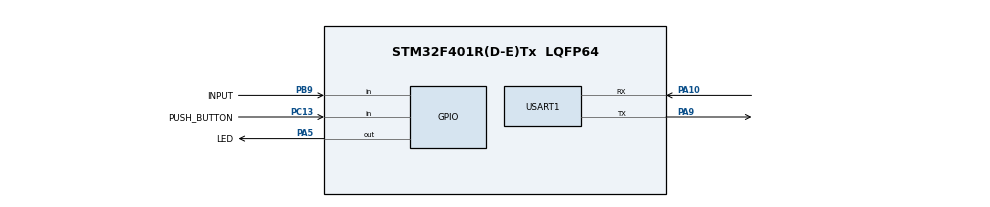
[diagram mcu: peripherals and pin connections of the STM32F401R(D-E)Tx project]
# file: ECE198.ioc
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Mcu.Family=STM32F4
Mcu.Name=STM32F401R(D-E)Tx
Mcu.Package=LQFP64
NVIC.PriorityGroup=NVIC_PRIORITYGROUP_0
NVIC.USART1_IRQn=true\:0\:0\:false\:false\:true\:true\:true\:true
PA10.Mode=Asynchronous
PA10.Signal=USART1_RX
PA13.GPIO_Label=TMS
PA13.Mode=Serial_Wire
PA13.Signal=SYS_JTMS-SWDIO
PA14.GPIO_Label=TCK
PA14.Mode=Serial_Wire
PA14.Signal=SYS_JTCK-SWCLK
PA5.GPIO_Label=LED
PA5.GPIO_Speed=GPIO_SPEED_FREQ_VERY_HIGH
PA5.Signal=GPIO_Output
PA9.Mode=Asynchronous
PA9.Signal=USART1_TX
PB9.GPIO_Label=INPUT
PB9.GPIO_PuPd=GPIO_PULLDOWN
PB9.Signal=GPIO_Input
PC13-ANTI_TAMP.GPIO_Label=PUSH_BUTTON
PC13-ANTI_TAMP.Signal=GPIO_Input
PC14-OSC32_IN.Signal=RCC_OSC32_IN
PC15-OSC32_OUT.Signal=RCC_OSC32_OUT
PH0\ -\ OSC_IN.Mode=HSE-External-Oscillator
PH0\ -\ OSC_IN.Signal=RCC_OSC_IN
PH1\ -\ OSC_OUT.Mode=HSE-External-Oscillator
PH1\ -\ OSC_OUT.Signal=RCC_OSC_OUT
ProjectManager.HeapSize=0x200
ProjectManager.StackSize=0x400
ProjectManager.TargetToolchain=STM32CubeIDE
RCC.48MHZClocksFreq_Value=48000000
RCC.AHBFreq_Value=84000000
RCC.APB1CLKDivider=RCC_HCLK_DIV2
RCC.APB1Freq_Value=42000000
RCC.APB1TimFreq_Value=84000000
RCC.APB2Freq_Value=84000000
RCC.APB2TimFreq_Value=84000000
RCC.CortexFreq_Value=84000000
RCC.HCLKFreq_Value=84000000
RCC.HSE_VALUE=8000000
RCC.HSI_VALUE=16000000
RCC.LSE_VALUE=32768
RCC.PLLN=336
RCC.PLLP=RCC_PLLP_DIV4
RCC.PLLQ=7
RCC.SYSCLKFreq_VALUE=84000000
RCC.SYSCLKSource=RCC_SYSCLKSOURCE_PLLCLK
RCC.VCOOutputFreq_Value=336000000
USART1.VirtualMode=VM_ASYNC
board=NUCLEO-F401RE

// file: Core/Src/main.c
/* USER CODE BEGIN Header */
/**
  ******************************************************************************
  * @file           : main.c
  * @brief          : Main program body
  ******************************************************************************
  * @attention
  *
  * <h2><center>&copy; Copyright (c) 2024 STMicroelectronics.
  * All rights reserved.</center></h2>
  *
  * This software component is licensed by ST under BSD 3-Clause license,
  * the "License"; You may not use this file except in compliance with the
  * License. You may obtain a copy of the License at:
  *                        opensource.org/licenses/BSD-3-Clause
  *
  ******************************************************************************
  */
/* USER CODE END Header */
#include "main.h"
#include <stdbool.h>

UART_HandleTypeDef huart1;

/* USER CODE BEGIN PV */
uint8_t rxData;
/* USER CODE END PV */

void SystemClock_Config(void);
static void MX_GPIO_Init(void);
static void MX_USART1_UART_Init(void);

int main(void)
{

  /* MCU Configuration--------------------------------------------------------*/

  /* Reset of all peripherals, Initializes the Flash interface and the Systick. */
  HAL_Init();

  /* Configure the system clock */
  SystemClock_Config();

  /* Initialize all configured peripherals */
  MX_GPIO_Init();
  MX_USART1_UART_Init();

  /* USER CODE BEGIN SysInit */

  while (1)
  {
	  HAL_GPIO_WritePin(LD2_GPIO_Port, LD2_Pin, GPIO_PIN_RESET);
    /* Read the state of the blue push button (connected to PC13) */
    if (HAL_GPIO_ReadPin(INPUT_GPIO_Port, INPUT_Pin) == GPIO_PIN_SET)  // Button is pressed
    {
    	while(true) {
			// Button pressed, activate buzzer and LED
			HAL_GPIO_WritePin(BUZZER_GPIO_Port, BUZZER_Pin, GPIO_PIN_SET);  // Turn buzzer ON
			HAL_GPIO_WritePin(LD2_GPIO_Port, LD2_Pin, GPIO_PIN_SET);        // Turn on LED

			// Send "Calling 911" message via UART
			char message[] = "Calling 911";
			HAL_UART_Transmit(&huart1, (uint8_t*)message, sizeof(message) - 1, HAL_MAX_DELAY);

			// Start UART receive interrupt
			HAL_UART_Receive_IT(&huart1, &rxData, 1);

			// Add a delay to simulate the buzzer sound duration (e.g., 2 seconds)
			HAL_Delay(1500);

			// Deactivate buzzer and LED
			HAL_GPIO_WritePin(BUZZER_GPIO_Port, BUZZER_Pin, GPIO_PIN_RESET);  // Turn buzzer OFF
			HAL_GPIO_WritePin(LD2_GPIO_Port, LD2_Pin, GPIO_PIN_RESET);        // Turn off LED

			// Add a small delay to debounce the button (optional)
			HAL_Delay(1500);
    	}
    }
  }
  /* USER CODE END 2 */
}

void SystemClock_Config(void)
{
  RCC_OscInitTypeDef RCC_OscInitStruct = {0};
  RCC_ClkInitTypeDef RCC_ClkInitStruct = {0};

  /* Enable power clock */
  __HAL_RCC_PWR_CLK_ENABLE();
  __HAL_PWR_VOLTAGESCALING_CONFIG(PWR_REGULATOR_VOLTAGE_SCALE2);

  /* Configure the HSI oscillator */
  RCC_OscInitStruct.OscillatorType = RCC_OSCILLATORTYPE_HSI;
  RCC_OscInitStruct.HSIState = RCC_HSI_ON;
  RCC_OscInitStruct.HSICalibrationValue = RCC_HSICALIBRATION_DEFAULT;
  RCC_OscInitStruct.PLL.PLLState = RCC_PLL_NONE;  // Disable PLL as we don't need it
  if (HAL_RCC_OscConfig(&RCC_OscInitStruct) != HAL_OK)
  {
    Error_Handler();
  }

  /* Initialize the system clocks */
  RCC_ClkInitStruct.ClockType = RCC_CLOCKTYPE_SYSCLK | RCC_CLOCKTYPE_HCLK |
                                RCC_CLOCKTYPE_PCLK1 | RCC_CLOCKTYPE_PCLK2;
  RCC_ClkInitStruct.SYSCLKSource = RCC_SYSCLKSOURCE_HSI;  // Use HSI as system clock
  RCC_ClkInitStruct.AHBCLKDivider = RCC_SYSCLK_DIV1;       // No division
  RCC_ClkInitStruct.APB1CLKDivider = RCC_HCLK_DIV2;        // Divide APB1 clock
  RCC_ClkInitStruct.APB2CLKDivider = RCC_HCLK_DIV1;        // No division for APB2

  if (HAL_RCC_ClockConfig(&RCC_ClkInitStruct, FLASH_LATENCY_0) != HAL_OK)
  {
    Error_Handler();
  }
}

static void MX_USART1_UART_Init(void)
{
  huart1.Instance = USART1;
  huart1.Init.BaudRate = 9600;
  huart1.Init.WordLength = UART_WORDLENGTH_8B;
  huart1.Init.StopBits = UART_STOPBITS_1;
  huart1.Init.Parity = UART_PARITY_NONE;
  huart1.Init.Mode = UART_MODE_TX_RX;
  huart1.Init.HwFlowCtl = UART_HWCONTROL_NONE;
  huart1.Init.OverSampling = UART_OVERSAMPLING_16;
  if (HAL_UART_Init(&huart1) != HAL_OK)
  {
    Error_Handler();
  }
}

static void MX_GPIO_Init(void)
{
  GPIO_InitTypeDef GPIO_InitStruct = {0};

  /* GPIO Ports Clock Enable */
  __HAL_RCC_GPIOC_CLK_ENABLE();
  __HAL_RCC_GPIOD_CLK_ENABLE();
  __HAL_RCC_GPIOA_CLK_ENABLE();
  __HAL_RCC_GPIOB_CLK_ENABLE();

  /*Configure GPIO pin Output Level */
  HAL_GPIO_WritePin(LD2_GPIO_Port, LD2_Pin, GPIO_PIN_SET);

  /*Configure GPIO pin : PC13 (blue push button) */
  GPIO_InitStruct.Pin = BUTTON_Pin;
  GPIO_InitStruct.Mode = GPIO_MODE_INPUT;
  GPIO_InitStruct.Pull = GPIO_PULLUP;  // Enable internal pull-up resistor
  HAL_GPIO_Init(GPIOC, &GPIO_InitStruct);

  /*Configure GPIO pin : LD2_Pin */
  GPIO_InitStruct.Pin = LD2_Pin;
  GPIO_InitStruct.Mode = GPIO_MODE_OUTPUT_PP;
  GPIO_InitStruct.Pull = GPIO_NOPULL;
  GPIO_InitStruct.Speed = GPIO_SPEED_FREQ_LOW;
  HAL_GPIO_Init(LD2_GPIO_Port, &GPIO_InitStruct);

  /* Configure GPIO pin : BUZZER_Pin */
  GPIO_InitStruct.Pin = BUZZER_Pin;
  GPIO_InitStruct.Mode = GPIO_MODE_OUTPUT_PP;
  GPIO_InitStruct.Pull = GPIO_NOPULL;
  GPIO_InitStruct.Speed = GPIO_SPEED_FREQ_LOW;
  HAL_GPIO_Init(BUZZER_GPIO_Port, &GPIO_InitStruct);

  GPIO_InitStruct.Pin = INPUT_Pin;
  GPIO_InitStruct.Mode = GPIO_MODE_INPUT;
  GPIO_InitStruct.Pull = GPIO_PULLDOWN;
  HAL_GPIO_Init(GPIOB, &GPIO_InitStruct);

  /* EXTI interrupt init */
  HAL_NVIC_SetPriority(EXTI15_10_IRQn, 0, 0);
  HAL_NVIC_EnableIRQ(EXTI15_10_IRQn);
}

void Error_Handler(void)
{
  __disable_irq();
  while (1)
  {
  }
}

void HAL_UART_RxCpltCallback(UART_HandleTypeDef *huart)
{
  if (huart->Instance == USART1)
  {
    HAL_UART_Receive_IT(&huart1, &rxData, 1);
  }
}
